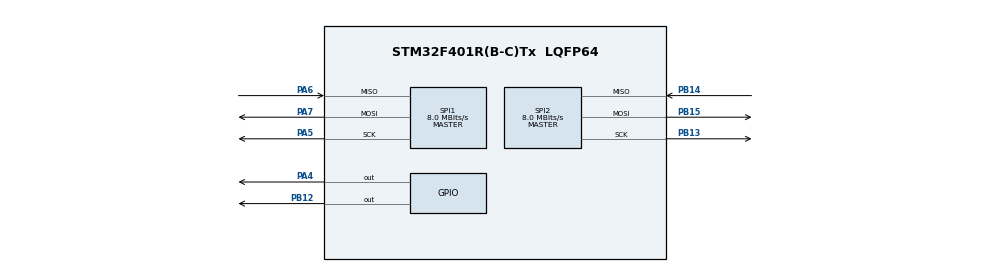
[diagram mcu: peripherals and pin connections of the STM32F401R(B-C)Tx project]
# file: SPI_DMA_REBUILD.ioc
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Dma.Request0=SPI2_RX
Dma.Request1=SPI2_TX
Dma.Request2=SPI1_RX
Dma.Request3=SPI1_TX
Dma.SPI1_RX.2.Direction=DMA_PERIPH_TO_MEMORY
Dma.SPI1_RX.2.FIFOMode=DMA_FIFOMODE_DISABLE
Dma.SPI1_RX.2.Instance=DMA2_Stream0
Dma.SPI1_RX.2.MemDataAlignment=DMA_MDATAALIGN_BYTE
Dma.SPI1_RX.2.MemInc=DMA_MINC_ENABLE
Dma.SPI1_RX.2.Mode=DMA_NORMAL
Dma.SPI1_RX.2.PeriphDataAlignment=DMA_PDATAALIGN_BYTE
Dma.SPI1_RX.2.PeriphInc=DMA_PINC_DISABLE
Dma.SPI1_RX.2.Priority=DMA_PRIORITY_LOW
Dma.SPI1_TX.3.Direction=DMA_MEMORY_TO_PERIPH
Dma.SPI1_TX.3.FIFOMode=DMA_FIFOMODE_DISABLE
Dma.SPI1_TX.3.Instance=DMA2_Stream3
Dma.SPI1_TX.3.MemDataAlignment=DMA_MDATAALIGN_BYTE
Dma.SPI1_TX.3.MemInc=DMA_MINC_ENABLE
Dma.SPI1_TX.3.Mode=DMA_NORMAL
Dma.SPI1_TX.3.PeriphDataAlignment=DMA_PDATAALIGN_BYTE
Dma.SPI1_TX.3.PeriphInc=DMA_PINC_DISABLE
Dma.SPI1_TX.3.Priority=DMA_PRIORITY_LOW
Dma.SPI2_RX.0.Direction=DMA_PERIPH_TO_MEMORY
Dma.SPI2_RX.0.FIFOMode=DMA_FIFOMODE_DISABLE
Dma.SPI2_RX.0.Instance=DMA1_Stream3
Dma.SPI2_RX.0.MemDataAlignment=DMA_MDATAALIGN_BYTE
Dma.SPI2_RX.0.MemInc=DMA_MINC_ENABLE
Dma.SPI2_RX.0.Mode=DMA_NORMAL
Dma.SPI2_RX.0.PeriphDataAlignment=DMA_PDATAALIGN_BYTE
Dma.SPI2_RX.0.PeriphInc=DMA_PINC_DISABLE
Dma.SPI2_RX.0.Priority=DMA_PRIORITY_LOW
Dma.SPI2_TX.1.Direction=DMA_MEMORY_TO_PERIPH
Dma.SPI2_TX.1.FIFOMode=DMA_FIFOMODE_DISABLE
Dma.SPI2_TX.1.Instance=DMA1_Stream4
Dma.SPI2_TX.1.MemDataAlignment=DMA_MDATAALIGN_BYTE
Dma.SPI2_TX.1.MemInc=DMA_MINC_ENABLE
Dma.SPI2_TX.1.Mode=DMA_NORMAL
Dma.SPI2_TX.1.PeriphDataAlignment=DMA_PDATAALIGN_BYTE
Dma.SPI2_TX.1.PeriphInc=DMA_PINC_DISABLE
Dma.SPI2_TX.1.Priority=DMA_PRIORITY_LOW
Mcu.Family=STM32F4
Mcu.Name=STM32F401R(B-C)Tx
Mcu.Package=LQFP64
NVIC.DMA1_Stream3_IRQn=true\:0\:0\:false\:false\:true\:false\:true\:true
NVIC.DMA1_Stream4_IRQn=true\:0\:0\:false\:false\:true\:false\:true\:true
NVIC.DMA2_Stream0_IRQn=true\:0\:0\:false\:false\:true\:false\:true\:true
NVIC.DMA2_Stream3_IRQn=true\:0\:0\:false\:false\:true\:false\:true\:true
NVIC.PriorityGroup=NVIC_PRIORITYGROUP_4
NVIC.SPI1_IRQn=true\:0\:0\:false\:false\:true\:true\:true\:true
NVIC.SPI2_IRQn=true\:0\:0\:false\:false\:true\:true\:true\:true
PA13.Mode=Serial_Wire
PA13.Signal=SYS_JTMS-SWDIO
PA14.Mode=Serial_Wire
PA14.Signal=SYS_JTCK-SWCLK
PA4.PinState=GPIO_PIN_SET
PA4.Signal=GPIO_Output
PA5.Mode=Full_Duplex_Master
PA5.Signal=SPI1_SCK
PA6.Mode=Full_Duplex_Master
PA6.Signal=SPI1_MISO
PA7.Mode=Full_Duplex_Master
PA7.Signal=SPI1_MOSI
PB12.PinState=GPIO_PIN_SET
PB12.Signal=GPIO_Output
PB13.Mode=Full_Duplex_Master
PB13.Signal=SPI2_SCK
PB14.Mode=Full_Duplex_Master
PB14.Signal=SPI2_MISO
PB15.Mode=Full_Duplex_Master
PB15.Signal=SPI2_MOSI
PH0\ -\ OSC_IN.Mode=HSE-External-Oscillator
PH0\ -\ OSC_IN.Signal=RCC_OSC_IN
PH1\ -\ OSC_OUT.Mode=HSE-External-Oscillator
PH1\ -\ OSC_OUT.Signal=RCC_OSC_OUT
ProjectManager.HeapSize=0x200
ProjectManager.StackSize=0x400
ProjectManager.TargetToolchain=MDK-ARM V5.32
RCC.AHBFreq_Value=16000000
RCC.APB1Freq_Value=16000000
RCC.APB2Freq_Value=16000000
RCC.CortexFreq_Value=16000000
RCC.HSE_VALUE=25000000
RCC.HSI_VALUE=16000000
RCC.LSE_VALUE=32768
RCC.SYSCLKFreq_VALUE=16000000
RCC.VCOOutputFreq_Value=192000000
SPI1.CalculateBaudRate=8.0 MBits/s
SPI1.Direction=SPI_DIRECTION_2LINES
SPI1.Mode=SPI_MODE_MASTER
SPI1.VirtualType=VM_MASTER
SPI2.CalculateBaudRate=8.0 MBits/s
SPI2.Direction=SPI_DIRECTION_2LINES
SPI2.Mode=SPI_MODE_MASTER
SPI2.VirtualType=VM_MASTER
board=custom

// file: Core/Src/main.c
/* USER CODE BEGIN Header */
/**
 ******************************************************************************
 * @file           : main.c
 * @brief          : Main program body
 ******************************************************************************
 * @attention
 *
 * Copyright (c) 2023 STMicroelectronics.
 * All rights reserved.
 *
 * This software is licensed under terms that can be found in the LICENSE file
 * in the root directory of this software component.
 * If no LICENSE file comes with this software, it is provided AS-IS.
 *
 ******************************************************************************
 */
/* USER CODE END Header */
#include "main.h"
#include "dma.h"
#include "spi.h"
#include "gpio.h"

/* USER CODE BEGIN Includes */
#include "w25q64.h"
#include "DataPackage.h"
#include "spi1_api.h"
/* USER CODE END Includes */

/* USER CODE BEGIN PV */
extern uint8_t flag;
extern uint8_t DataPack[1626];  // 数据包缓存
extern uint16_t header, data_rows;
uint8_t ID[4];                  // 设备ID缓存数组
uint32_t i;
uint8_t test_data[1620];        // 测试数据缓存
uint8_t rdata[1626] = {0};      // 读数据包缓存
uint16_t crc_code;              // CRC校验码
/* USER CODE END PV */

void SystemClock_Config(void);

int main(void)
{

    /* MCU Configuration--------------------------------------------------------*/

    /* Reset of all peripherals, Initializes the Flash interface and the Systick. */
    HAL_Init();

    /* Configure the system clock */
    SystemClock_Config();

    /* Initialize all configured peripherals */
    MX_GPIO_Init();
    MX_DMA_Init();
    MX_SPI2_Init();
    MX_SPI1_Init();
    /* USER CODE BEGIN 2 */
    BSP_W25Qx_Init();

    uint16_t i;
    for (i = 0; i < 1620; i++) {
        test_data[i] = i;
    }

    crc_code = CRC16_CALCULATE(test_data, 1620);

    // 封装数据包
    PackageData(header, data_rows, test_data, crc_code);

    // 写测试数据并读取
    BSP_W25Qx_EraseWrite(DataPack, 0x00, sizeof(DataPack));
    BSP_W25Qx_ReadDMA(rdata, 0x00, sizeof(rdata));
    while(flag)
    {
        HAL_Delay(1);
    }
    flag = 1;       // DMA回调标志

    // // SPI1 DMA收发测试
    // SPI1_SendDataPack(test_data);
    // while(flag)
    // {
    //     HAL_Delay(1);
    // }
    // flag = 1;       // DMA回调标志

    // SPI1_ReceiveDataPack(rdata);
    // while(flag)
    // {
    //     HAL_Delay(1);
    // }
    // flag = 1;       // DMA回调标志

    // SPI1_TxRxDataPack(test_data,rdata);
    // while(flag)
    // {
    //     HAL_Delay(1);
    // }
    // flag = 1;       // DMA回调标志

    /* USER CODE END 2 */
    data_rows = 0;
    /* Infinite loop */
    while (1)
    {
        SPI1_SendDataPack(test_data);
        data_rows++;
		HAL_Delay(1000);
        /* USER CODE END WHILE */

    }
}

void SystemClock_Config(void)
{
    RCC_OscInitTypeDef RCC_OscInitStruct = {0};
    RCC_ClkInitTypeDef RCC_ClkInitStruct = {0};

    /** Configure the main internal regulator output voltage
     */
    __HAL_RCC_PWR_CLK_ENABLE();
    __HAL_PWR_VOLTAGESCALING_CONFIG(PWR_REGULATOR_VOLTAGE_SCALE2);

    /** Initializes the RCC Oscillators according to the specified parameters
     * in the RCC_OscInitTypeDef structure.
     */
    RCC_OscInitStruct.OscillatorType = RCC_OSCILLATORTYPE_HSE;
    RCC_OscInitStruct.HSEState       = RCC_HSE_ON;
    RCC_OscInitStruct.PLL.PLLState   = RCC_PLL_ON;
    RCC_OscInitStruct.PLL.PLLSource  = RCC_PLLSOURCE_HSE;
    RCC_OscInitStruct.PLL.PLLM       = 6;
    RCC_OscInitStruct.PLL.PLLN       = 84;
    RCC_OscInitStruct.PLL.PLLP       = RCC_PLLP_DIV2;
    RCC_OscInitStruct.PLL.PLLQ       = 4;
    if (HAL_RCC_OscConfig(&RCC_OscInitStruct) != HAL_OK) {
        Error_Handler();
    }

    /** Initializes the CPU, AHB and APB buses clocks
     */
    RCC_ClkInitStruct.ClockType      = RCC_CLOCKTYPE_HCLK | RCC_CLOCKTYPE_SYSCLK | RCC_CLOCKTYPE_PCLK1 | RCC_CLOCKTYPE_PCLK2;
    RCC_ClkInitStruct.SYSCLKSource   = RCC_SYSCLKSOURCE_PLLCLK;
    RCC_ClkInitStruct.AHBCLKDivider  = RCC_SYSCLK_DIV1;
    RCC_ClkInitStruct.APB1CLKDivider = RCC_HCLK_DIV2;
    RCC_ClkInitStruct.APB2CLKDivider = RCC_HCLK_DIV1;

    if (HAL_RCC_ClockConfig(&RCC_ClkInitStruct, FLASH_LATENCY_2) != HAL_OK) {
        Error_Handler();
    }
}

void Error_Handler(void)
{
    __disable_irq();
    while (1) {
    }
}
